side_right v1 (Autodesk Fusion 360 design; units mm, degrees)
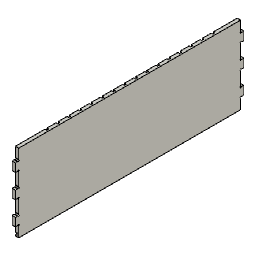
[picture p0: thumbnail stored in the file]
description: Part Number
part number: side_right
base_feature "Base Feature"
